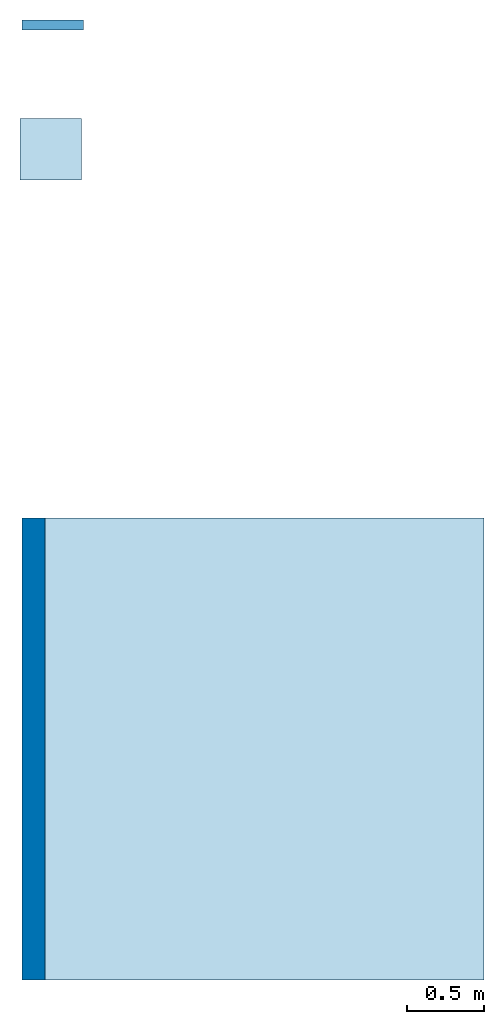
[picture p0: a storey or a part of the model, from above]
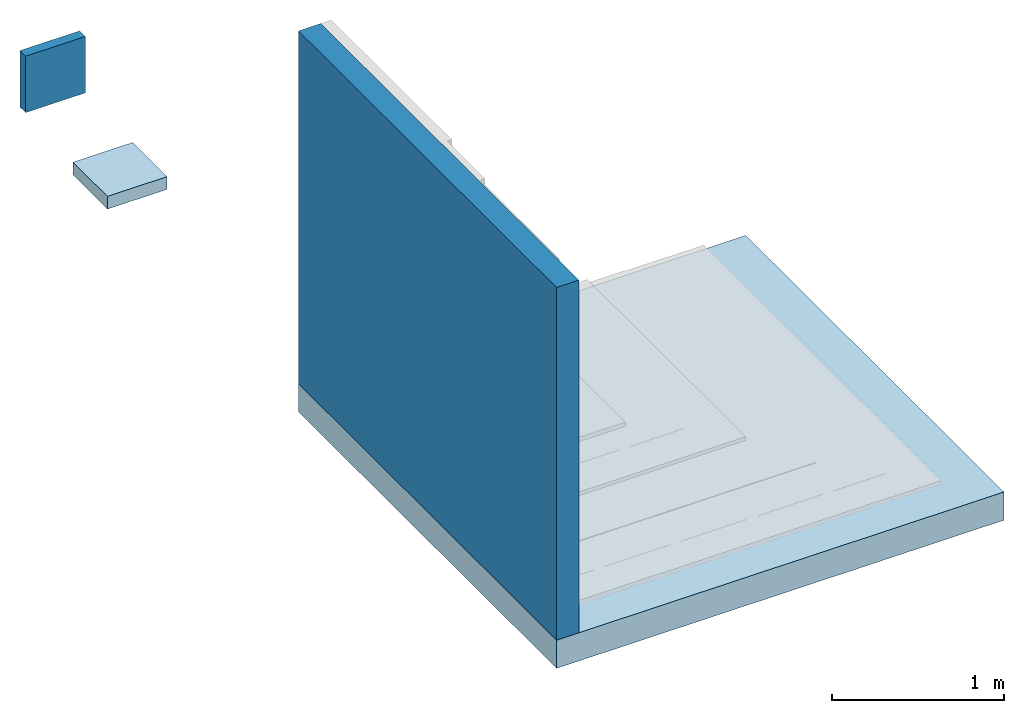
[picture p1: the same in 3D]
Properties of the parts of a building model (IFC2X3)

# File
Description: ViewDefinition [CoordinationView_V2.0], RevitIdentifiers [VersionGUID: 97d3df66-b993-4e9b-90aa-65fc51f4724e, NumberOfSaves: 18], CoordinateReference [CoordinateBase: Coordenadas compartilhadas]
File name: 0001
Time: 2025-02-04T09:52:35
Written by: ODA IFC SDK 22.8
Made in: 22.1.50.17 - Exporter 22.6.2.0 - IU alternativa 22.6.2.0

# IfcProject, 0001
LongName: Sauna - Manta Asfáltica TORODIN 4PP + VITKOTE ELASTIC; Phase: Status do projeto

# IfcSite, Default
RefLatitude: 42, 21, 31, 181944; RefLongitude: -71, -3, -24, -263304; RefElevation: 0 m

# IfcBuilding
Pset_BuildingCommon - NumberOfStoreys: 1; IsLandmarked: no

# IfcBuildingStorey: Nível:Cabeça de 8 mm, ARQ Térreo
LongName: ARQ Térreo; Elevation: -0.0025238 m

# IfcBuildingElementProxy: IMPER:IMPER:433934, IMPER:IMPER:433934:IMPER:433934 : IMPER:IMPER:433934:291594
In: ARQ Térreo
Type - Material: #XPS, #Vitkote Elastic, #argamassa, #Primer Adeflex, # Torodin 4mm - TIPO III - Classe A, #proteção mecânica, #Tela Plástica, #camada separadora, #selante
Type - Pset_BuildingElementProxyCommon - Reference: IMPER
Type - Pset_QuantityTakeOff - Reference: IMPER
Type - Pset_ProvisionForVoid - Width: 0.952886 m; Height: 0.00103887 m; Depth: 2.66 m
Pset_BuildingElementProxyCommon - sets with these values: 2

# IfcSlab: Piso:IMPH_T4PP, Piso:IMPH_T4PP:293202
In: ARQ Térreo
Type - PredefinedType: FLOOR; Material: #proteção mecânica 0.03 m, #XPS 0.025 m, # Torodin 4mm - TIPO III - Classe A 0.004 m, #Primer Adeflex 0.001 m, #argamassa 0.03 m
Type - Pset_SlabCommon - IsExternal: no
Pset_QuantityTakeOff - Reference: IMPH_T4PP; sets with these values: 2
Pset_SlabCommon - LoadBearing: no; PitchAngle: 0 deg; Reference: IMPH_T4PP

# IfcSlab: Piso:Piso:LAJE CONCRETO, Piso:Piso:LAJE CONCRETO:293183
In: ARQ Térreo
Type - PredefinedType: FLOOR; Material: #concreto 0.2 m
Type - Pset_SlabCommon - IsExternal: no
Pset_QuantityTakeOff - Reference: Piso:LAJE CONCRETO; sets with these values: 2
Pset_SlabCommon - Reference: Piso:LAJE CONCRETO; LoadBearing: no; PitchAngle: 0 deg

# IfcWallStandardCase: Parede básica:IMPV_VITKOTE ELASTIC, Parede básica:IMPV_T4PP:459587
In: ARQ Térreo
Type - PredefinedType: STANDARD; Material: #proteção mecânica 0.03 m, #XPS 0.025 m, #Vitkote Elastic 0.001 m, #argamassa 0.01 m
Type - Pset_WallCommon - IsExternal: yes; ThermalTransmittance: 17 kg/K/s3
Pset_QuantityTakeOff - Reference: IMPV_T4PP; sets with these values: 2
Pset_WallCommon - LoadBearing: no; ExtendToStructure: no; Reference: IMPV_T4PP

# IfcWallStandardCase: Parede básica:Parede básica:Parede Concreto, Parede básica:Parede Concreto:395312
In: ARQ Térreo
Type - PredefinedType: STANDARD; Material: #concreto 0.15 m
Type - Pset_WallCommon - IsExternal: yes; ThermalTransmittance: 6.97333 kg/K/s3
Pset_QuantityTakeOff - Reference: Parede Concreto; sets with these values: 2
Pset_WallCommon - LoadBearing: no; Reference: Parede Concreto; ExtendToStructure: no
